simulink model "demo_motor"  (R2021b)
settings: Solver=FixedStepDiscrete  StartTime=0.0  StopTime=inf  FixedStep=0.01  RelTol=1e-3
libraries: MotorDriver_Velocity_Control_lib x1, CAN_Init_lib x1, MotorDriver_Mode_Choice_lib x1, MotorDriver_Reset_lib x1, sculib x1, delay_ms_lib x1, sldrtlib x1, Now_lib x1

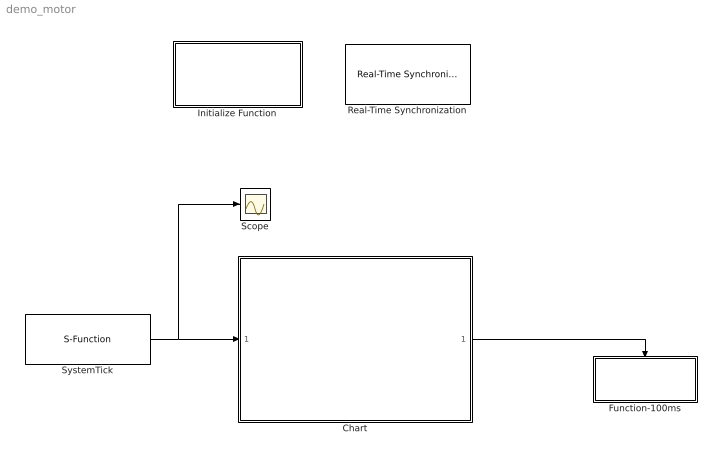
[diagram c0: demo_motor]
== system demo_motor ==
  Chart : Stateflow chart  TreatAsAtomicUnit=on
  Function-100ms : Subsystem  TreatAsAtomicUnit=on
  Initialize Function : Subsystem  TreatAsAtomicUnit=on
  Real-Time Synchronization : sldrtlib/Real-Time Synchronization  Commented=on  SampleTime=-1  MaxMissedTicks=inf  ShowMissedTicks=off  YieldWhenWaiting=off
  Scope : Scope
  SystemTick : Now_lib/S-Function  SFunctionModules=''
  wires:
  SystemTick/1 -> Scope/1, Chart/1(systick)
  Chart/1(call_100ms()) -> Function-100ms/Trigger

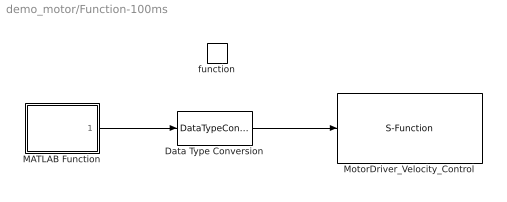
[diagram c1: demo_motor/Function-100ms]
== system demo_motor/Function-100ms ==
  function : TriggerPort  TriggerType=function-call  VariantControl=(inherit)
  Data Type Conversion : DataTypeConversion  OutDataTypeStr=int16
  MATLAB Function : MATLAB Function  TreatAsAtomicUnit=on
  MotorDriver_Velocity_Control : MotorDriver_Velocity_Control_lib/S-Function  group=0  number=1
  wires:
  MATLAB Function/1(y) -> Data Type Conversion/1
  Data Type Conversion/1 -> MotorDriver_Velocity_Control/1

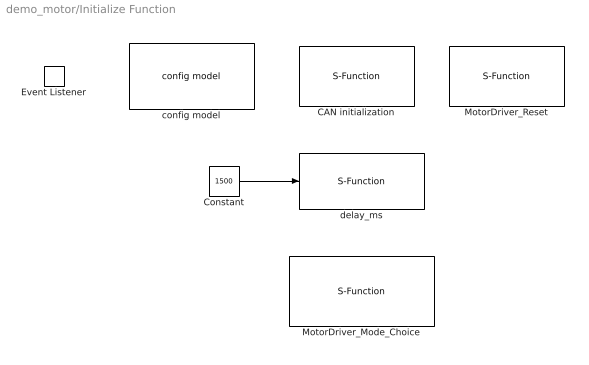
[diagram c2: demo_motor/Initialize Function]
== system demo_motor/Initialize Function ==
  CAN initialization : CAN_Init_lib/S-Function  Priority=1  baudrate=100
  Constant : Constant  Value=1500  OutDataTypeStr=uint16
  Event Listener : EventListener  DisableCoverage=on  EventName=reset
  MotorDriver_Mode_Choice : MotorDriver_Mode_Choice_lib/S-Function  Priority=4  group=0  number=1  mode=3-速度
  MotorDriver_Reset : MotorDriver_Reset_lib/S-Function  Priority=2  group=0  number=0
  config model : sculib/SCU001/config model  Priority=0  iap=Uart2  uart1_baudrate=9600  uart2_baudrate=115200  rs485_1_baudrate=9600  rs485_2_baudrate=9600  rs485_1_read_interval=10  rs485_2_read_interval=10
  delay_ms : delay_ms_lib/S-Function  Priority=3  vu16=0
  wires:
  Constant/1 -> delay_ms/1

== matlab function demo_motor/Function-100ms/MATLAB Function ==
function y = fcn

persistent tmp_cnt;
persistent tmp_dir;

if isempty(tmp_cnt)
    tmp_cnt = 0;
    tmp_dir = 0;
end

if tmp_dir == 0
    tmp_cnt = tmp_cnt + 1000;
    if tmp_cnt >= 30000
        tmp_dir = 1;
    end
else
    tmp_cnt = tmp_cnt - 1000;
    if tmp_cnt <= -30000
        tmp_dir = 0;
    end
end

y = tmp_cnt;

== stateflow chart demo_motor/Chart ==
  (default) -> (junction 14) : % 任务调用
  (junction 14) -> (junction 15) : [rem(systick,10)==0]
  (junction 15) -> (junction 16) : {call_100ms}
  (junction 14) -> (junction 16)
  data: systick input
  events: output FUNCTION_CALL_EVENT
